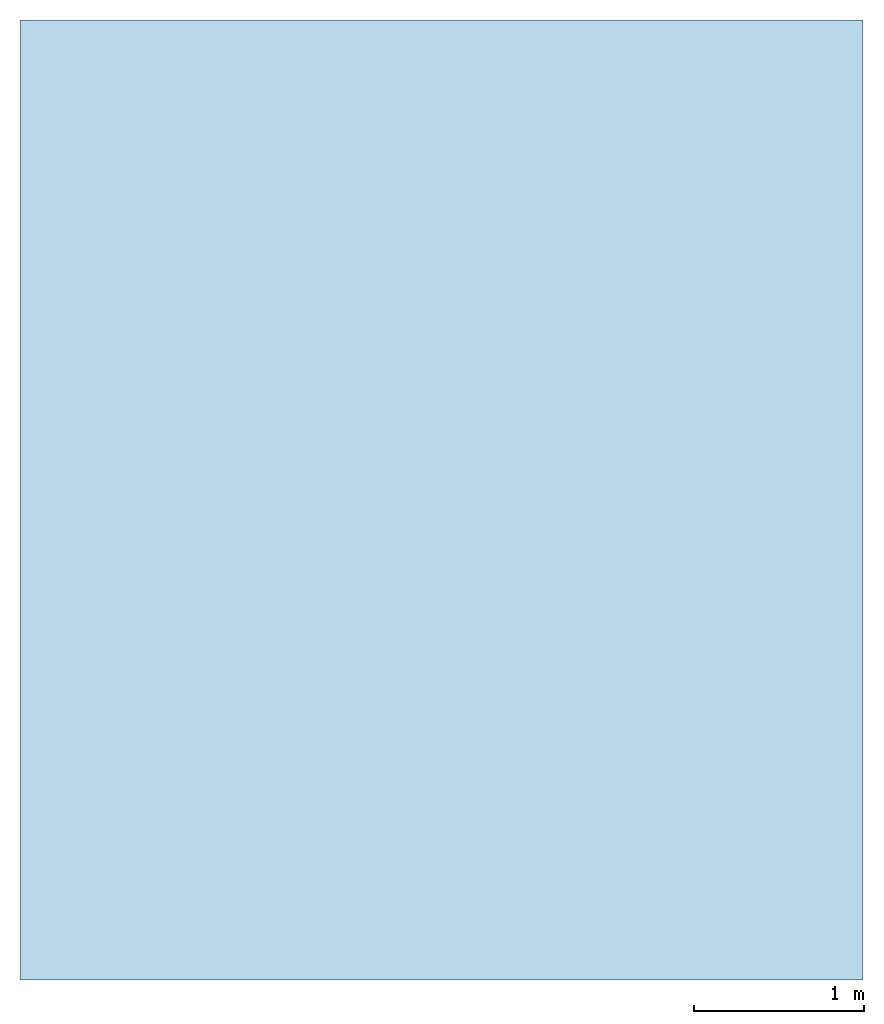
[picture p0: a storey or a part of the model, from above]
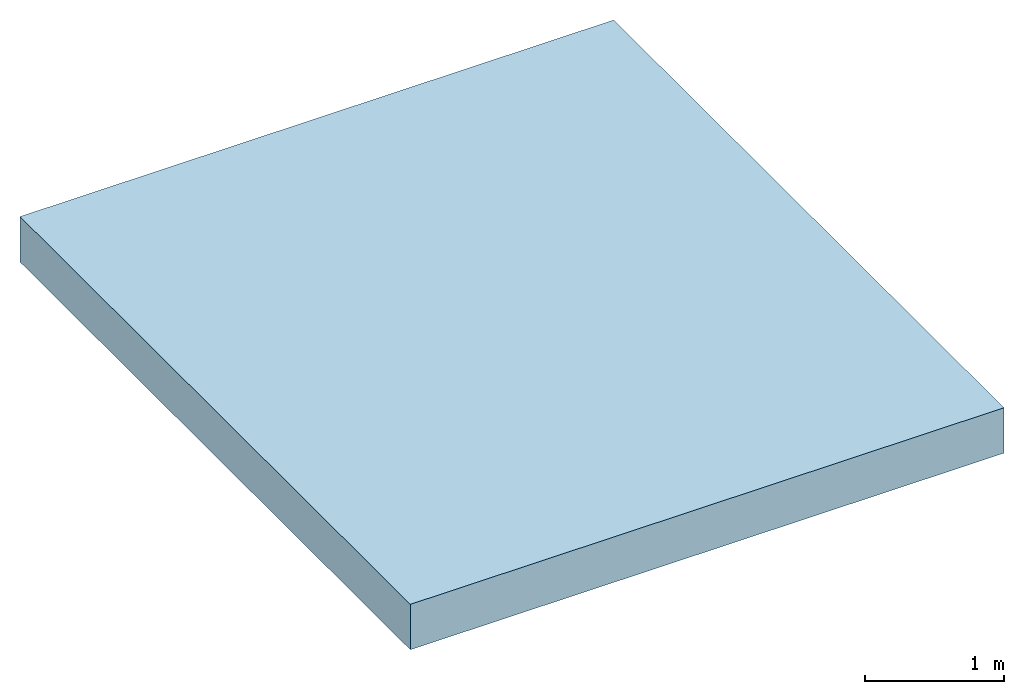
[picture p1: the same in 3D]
Properties of the parts of a building model (IFC2X3)

# File
Description: ViewDefinition [CoordinationView]
File name: 4984 - 6m external radius unit.ifc
Time: 2013-09-12T12:53:00
Written by: Autodesk Revit 2013
Made in: 20120221_2030(x64)

# IfcProject, Project Number
LongName: Project Name; Phase: Project Status

# IfcSite, Default
RefLatitude: 42, 21, 30, 344238; RefLongitude: -71, -3, -35, -194702; RefElevation: 0 mm

# IfcBuilding
Pset_BuildingCommon - NumberOfStoreys: 2
Other - Project Address: Enter address here; Project Number: Project Number; Project Issue Date: Issue Date; Project Status: Project Status; Client Name: Owner; Project Name: Project Name

# IfcBuildingStorey (2)
Constraints - Elevation Base: 0
Graphics - Symbol at End 1 Default: no; Line Pattern: Center; Symbol: M_Level Head - Circle: M_Level Head - Circle; Symbol at End 2 Default: yes; Line Weight: 1; Color: 0
Identity Data - Building Story: yes; Structural: no
Dimensions - Computation Height: 0 mm
Name | LongName = Name | Elevation (mm) = Constraints, Elevation (mm)
T.O. Fnd. Wall | T.O. Fnd. Wall | -300
Level 1 | Level 1 | 0

# IfcBuildingElementProxy: 4984 - 6m external radius unit, Civil-Drainage-Channel-ACO-KerbDrain-HB305 Part 2:4984 - 6m external radius unit:4984 - 6m external radius unit:263456
In: T.O. Fnd. Wall
Material: ACO Polymer Concrete.
Other - Revision: 1; CreatedBy: www.aco.co.uk
Data - Load Class: A 15 - D 400; Invert Depth: 280mm; Concrete Surround Volume - Load Class A 15 - D 400 - Concrete Pavement: N/A; Product Dimensions: 495mm x 150mm x 305mm (LxWxH); Drainage Slot Width: 50mm; Concrete Surround Volume - Load Class A 15 - D 400 - Grass or Asphalt Pavement: N/A; Installation - Concrete Grade: Refer to brochure; Product Weight: 27.8 Kg; Channel C.S.A: 0.02m²; Drainage Slot Intake area: 14592mm²/m; Connection Pipe O.D: N/A; Product Standard: BS EN 1433:2002, CE marked, Kitemarked; Hydraulic Performance: http://www.aco.co.uk/download.php?id=120; ACO Hydraulic Design Software: http://www.acodesign.co.uk
Green Building Properties - Channel Recyclable: Fully recyclable; End Cap Recyclable: N/A; Channel Recycled Material Content: 20% minimum; Access Cover/Frame Recycled Material Content: N/A; End Cap Recycled Material Content: N/A; Access Cover/Frame Recyclable: N/A
Construction - LH drop kerb- 6m ext rad: no; KDHB305 10-8m_external_mitre: no; KDHB305 6m _external_radius: yes; KDHB305 25-11m internal_mitre: no; KDHB305_quadrant: no; KDHB305 1.8m_radius: no; KDHB305 25-11m external_mitre: no; KDHB305 internal_angle: no; KDHB305 RH drop kerb-4999: no; flush drainable centre stone: no; KDHB305 7-6m external_mitre: no
Constraints - Moves With Nearby Elements: no; Level: Level: Level 1
Phasing - Phase Created: Phase 1
Dimensions - Volume: 12924372 mm3; 1.8m Radius unit Void Start: -4800 mm; 1.8m Radius Unit void End: -4805 mm; Straight Void Depth: -6000 mm; Staright Void Depth: -6005 mm; Void_Length: 483.47 mm; Void L Start: -3000 mm; Mite Long Side Length: 500 mm; Quadrant void End: 2620.7 mm; Curved LH Void Start: 3000 mm; Mitre Void End: -180 mm; Curved LH Void End: 3010 mm; Void L End: -3010 mm; Curved RH Void Start: -2980 mm; 6m Radius Unit Void end: -180 mm; 6m Radius unit void Start: 0 mm; Flush Drainable Centre Stone Void End: -4505 mm; Curved RH Void End: -3000 mm; mitre small length: 487 mm; Quadrant void Start: 2600.7 mm; Mitre Void Start: 0 mm; Void_Width: 155 mm; Flush Drainable Centre Stone Void Start: -4500 mm
Pset_BuildingElementProxyCommon - Reference: 4984 - 6m external radius unit
Identity Data - Address: ACO Business Park, Hitchin Road, Shefford, Bedfordshire, United Kingdom SG17 5TE; Manufacturer: ACO Technologies plc - ACO Water Management Division; Telephone: +44 (0)1462 816666; e-mail Technical: technical@aco.co.uk; Product Code: 4984; Price: POA - contact ACO; Product brochure: http://www.aco.co.uk/download.php?id=120; Cost: 0; URL: www.aco.co.uk; e-mail Sales: customersupport@aco.co.uk; Fax: +44 (0)1462 815895; Installation guidelines: http://www.aco.co.uk/download.php?id=120; Model Description: Combined kerb and drainage system; Product Page URL: http://www.aco.co.uk/product_detail.php?id=3; Maintenance guidelines: http://www.aco.co.uk/download.php?id=120; Type Comments: ACO KerbDrain HB305 half battered 6m external radius kerb 495mm long; Assembly Code: D2040; OmniClass Number: 23.70.50.24; Model: ACO KerbDrain HB305; Assembly Description: Rain Water Drainage; OmniClass Title: Rainwater Removal
Materials and Finishes - Connection Pipe Material: N/A; Access Cover/Frame Finish: N/A; Channel Colour: Grey; Channel Material: Vienite® Synthetic Resin Concrete; End Cap Colour: N/A; End Cap Material: N/A; Access Cover/Frame Colour: N/A; Access Cover/Frame Material: N/A; Connection Pipe Material Colour: N/A
General - TagNumber: 0.000000; SerialNumber: 0.000000

# IfcOpeningElement: Recess (6)
In: Level 1
Dimensions - Perimeter: 21157.2 mm; Area: 27858925 mm2; Thickness: 400 mm; Volume: 11129761858 mm3
Phasing - Phase Created: Phase 1
Constraints - Level: Level: Level 1; Height Offset From Level: 0 mm; Related to Mass: no; Room Bounding: yes
Structural - Structural: no; Enable Analytical Model: no
Analytical Properties - Absorptance: 0.1; Roughness: 1
Construction - Function: 0; Default Thickness: 400 mm
Graphics - Coarse Scale Fill Color: 0

# IfcSlab: Floor:Generic Floor - 400mm, Floor:Generic Floor - 400mm:184025
In: Level 1
PredefinedType: FLOOR; Material: Default Floor 400 mm
Dimensions - Perimeter: 21157.2 mm; Area: 27858925 mm2; Thickness: 400 mm; Volume: 11129761858 mm3
Phasing - Phase Created: Phase 1
Constraints - Level: Level: Level 1; Height Offset From Level: 0 mm; Related to Mass: no; Room Bounding: yes
Structural - Structural: no; Enable Analytical Model: no
Pset_SlabCommon - Reference: Generic Floor - 400mm; IsExternal: no; LoadBearing: yes
Analytical Properties - Absorptance: 0.1; Roughness: 1
Construction - Function: 0; Default Thickness: 400 mm
Graphics - Coarse Scale Fill Color: 0
